# Generated deterministically by seda-macro-lef-normalizer-v1; recipe orfs-ng45-fakeram-metal3-coupledl2-pg-v1.
VERSION 5.8 ;
BUSBITCHARS "[]" ;
DIVIDERCHAR "/" ;

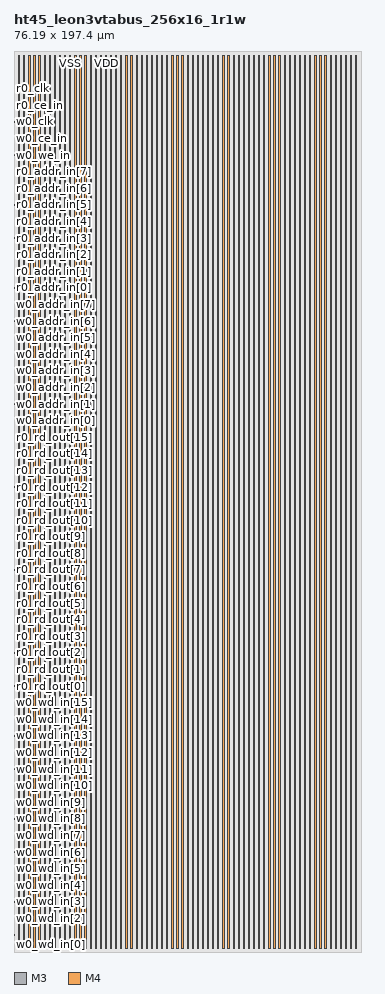
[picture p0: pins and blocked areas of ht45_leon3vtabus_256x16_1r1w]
MACRO ht45_leon3vtabus_256x16_1r1w
  FOREIGN ht45_leon3vtabus_256x16_1r1w 0 0 ;
  CLASS BLOCK ;
  ORIGIN 0 0 ;
  SIZE 76.19 BY 197.4 ;
  SYMMETRY X Y R90 ;
  PIN w0_wd_in[0]
    DIRECTION INPUT ;
    USE SIGNAL ;
    SHAPE ABUTMENT ;
    PORT
      LAYER M3 ;
      RECT 0 0.035 0.07 0.105 ;
    END
  END w0_wd_in[0]
  PIN w0_wd_in[1]
    DIRECTION INPUT ;
    USE SIGNAL ;
    SHAPE ABUTMENT ;
    PORT
      LAYER M3 ;
      RECT 0 3.675 0.07 3.745 ;
    END
  END w0_wd_in[1]
  PIN w0_wd_in[2]
    DIRECTION INPUT ;
    USE SIGNAL ;
    SHAPE ABUTMENT ;
    PORT
      LAYER M3 ;
      RECT 0 7.315 0.07 7.385 ;
    END
  END w0_wd_in[2]
  PIN w0_wd_in[3]
    DIRECTION INPUT ;
    USE SIGNAL ;
    SHAPE ABUTMENT ;
    PORT
      LAYER M3 ;
      RECT 0 10.955 0.07 11.025 ;
    END
  END w0_wd_in[3]
  PIN w0_wd_in[4]
    DIRECTION INPUT ;
    USE SIGNAL ;
    SHAPE ABUTMENT ;
    PORT
      LAYER M3 ;
      RECT 0 14.595 0.07 14.665 ;
    END
  END w0_wd_in[4]
  PIN w0_wd_in[5]
    DIRECTION INPUT ;
    USE SIGNAL ;
    SHAPE ABUTMENT ;
    PORT
      LAYER M3 ;
      RECT 0 18.235 0.07 18.305 ;
    END
  END w0_wd_in[5]
  PIN w0_wd_in[6]
    DIRECTION INPUT ;
    USE SIGNAL ;
    SHAPE ABUTMENT ;
    PORT
      LAYER M3 ;
      RECT 0 21.875 0.07 21.945 ;
    END
  END w0_wd_in[6]
  PIN w0_wd_in[7]
    DIRECTION INPUT ;
    USE SIGNAL ;
    SHAPE ABUTMENT ;
    PORT
      LAYER M3 ;
      RECT 0 25.515 0.07 25.585 ;
    END
  END w0_wd_in[7]
  PIN w0_wd_in[8]
    DIRECTION INPUT ;
    USE SIGNAL ;
    SHAPE ABUTMENT ;
    PORT
      LAYER M3 ;
      RECT 0 29.155 0.07 29.225 ;
    END
  END w0_wd_in[8]
  PIN w0_wd_in[9]
    DIRECTION INPUT ;
    USE SIGNAL ;
    SHAPE ABUTMENT ;
    PORT
      LAYER M3 ;
      RECT 0 32.795 0.07 32.865 ;
    END
  END w0_wd_in[9]
  PIN w0_wd_in[10]
    DIRECTION INPUT ;
    USE SIGNAL ;
    SHAPE ABUTMENT ;
    PORT
      LAYER M3 ;
      RECT 0 36.435 0.07 36.505 ;
    END
  END w0_wd_in[10]
  PIN w0_wd_in[11]
    DIRECTION INPUT ;
    USE SIGNAL ;
    SHAPE ABUTMENT ;
    PORT
      LAYER M3 ;
      RECT 0 40.075 0.07 40.145 ;
    END
  END w0_wd_in[11]
  PIN w0_wd_in[12]
    DIRECTION INPUT ;
    USE SIGNAL ;
    SHAPE ABUTMENT ;
    PORT
      LAYER M3 ;
      RECT 0 43.715 0.07 43.785 ;
    END
  END w0_wd_in[12]
  PIN w0_wd_in[13]
    DIRECTION INPUT ;
    USE SIGNAL ;
    SHAPE ABUTMENT ;
    PORT
      LAYER M3 ;
      RECT 0 47.355 0.07 47.425 ;
    END
  END w0_wd_in[13]
  PIN w0_wd_in[14]
    DIRECTION INPUT ;
    USE SIGNAL ;
    SHAPE ABUTMENT ;
    PORT
      LAYER M3 ;
      RECT 0 50.995 0.07 51.065 ;
    END
  END w0_wd_in[14]
  PIN w0_wd_in[15]
    DIRECTION INPUT ;
    USE SIGNAL ;
    SHAPE ABUTMENT ;
    PORT
      LAYER M3 ;
      RECT 0 54.635 0.07 54.705 ;
    END
  END w0_wd_in[15]
  PIN r0_rd_out[0]
    DIRECTION OUTPUT ;
    USE SIGNAL ;
    SHAPE ABUTMENT ;
    PORT
      LAYER M3 ;
      RECT 0 58.275 0.07 58.345 ;
    END
  END r0_rd_out[0]
  PIN r0_rd_out[1]
    DIRECTION OUTPUT ;
    USE SIGNAL ;
    SHAPE ABUTMENT ;
    PORT
      LAYER M3 ;
      RECT 0 61.915 0.07 61.985 ;
    END
  END r0_rd_out[1]
  PIN r0_rd_out[2]
    DIRECTION OUTPUT ;
    USE SIGNAL ;
    SHAPE ABUTMENT ;
    PORT
      LAYER M3 ;
      RECT 0 65.555 0.07 65.625 ;
    END
  END r0_rd_out[2]
  PIN r0_rd_out[3]
    DIRECTION OUTPUT ;
    USE SIGNAL ;
    SHAPE ABUTMENT ;
    PORT
      LAYER M3 ;
      RECT 0 69.195 0.07 69.265 ;
    END
  END r0_rd_out[3]
  PIN r0_rd_out[4]
    DIRECTION OUTPUT ;
    USE SIGNAL ;
    SHAPE ABUTMENT ;
    PORT
      LAYER M3 ;
      RECT 0 72.835 0.07 72.905 ;
    END
  END r0_rd_out[4]
  PIN r0_rd_out[5]
    DIRECTION OUTPUT ;
    USE SIGNAL ;
    SHAPE ABUTMENT ;
    PORT
      LAYER M3 ;
      RECT 0 76.475 0.07 76.545 ;
    END
  END r0_rd_out[5]
  PIN r0_rd_out[6]
    DIRECTION OUTPUT ;
    USE SIGNAL ;
    SHAPE ABUTMENT ;
    PORT
      LAYER M3 ;
      RECT 0 80.115 0.07 80.185 ;
    END
  END r0_rd_out[6]
  PIN r0_rd_out[7]
    DIRECTION OUTPUT ;
    USE SIGNAL ;
    SHAPE ABUTMENT ;
    PORT
      LAYER M3 ;
      RECT 0 83.755 0.07 83.825 ;
    END
  END r0_rd_out[7]
  PIN r0_rd_out[8]
    DIRECTION OUTPUT ;
    USE SIGNAL ;
    SHAPE ABUTMENT ;
    PORT
      LAYER M3 ;
      RECT 0 87.395 0.07 87.465 ;
    END
  END r0_rd_out[8]
  PIN r0_rd_out[9]
    DIRECTION OUTPUT ;
    USE SIGNAL ;
    SHAPE ABUTMENT ;
    PORT
      LAYER M3 ;
      RECT 0 91.035 0.07 91.105 ;
    END
  END r0_rd_out[9]
  PIN r0_rd_out[10]
    DIRECTION OUTPUT ;
    USE SIGNAL ;
    SHAPE ABUTMENT ;
    PORT
      LAYER M3 ;
      RECT 0 94.675 0.07 94.745 ;
    END
  END r0_rd_out[10]
  PIN r0_rd_out[11]
    DIRECTION OUTPUT ;
    USE SIGNAL ;
    SHAPE ABUTMENT ;
    PORT
      LAYER M3 ;
      RECT 0 98.315 0.07 98.385 ;
    END
  END r0_rd_out[11]
  PIN r0_rd_out[12]
    DIRECTION OUTPUT ;
    USE SIGNAL ;
    SHAPE ABUTMENT ;
    PORT
      LAYER M3 ;
      RECT 0 101.955 0.07 102.025 ;
    END
  END r0_rd_out[12]
  PIN r0_rd_out[13]
    DIRECTION OUTPUT ;
    USE SIGNAL ;
    SHAPE ABUTMENT ;
    PORT
      LAYER M3 ;
      RECT 0 105.595 0.07 105.665 ;
    END
  END r0_rd_out[13]
  PIN r0_rd_out[14]
    DIRECTION OUTPUT ;
    USE SIGNAL ;
    SHAPE ABUTMENT ;
    PORT
      LAYER M3 ;
      RECT 0 109.235 0.07 109.305 ;
    END
  END r0_rd_out[14]
  PIN r0_rd_out[15]
    DIRECTION OUTPUT ;
    USE SIGNAL ;
    SHAPE ABUTMENT ;
    PORT
      LAYER M3 ;
      RECT 0 112.875 0.07 112.945 ;
    END
  END r0_rd_out[15]
  PIN w0_addr_in[0]
    DIRECTION INPUT ;
    USE SIGNAL ;
    SHAPE ABUTMENT ;
    PORT
      LAYER M3 ;
      RECT 0 116.515 0.07 116.585 ;
    END
  END w0_addr_in[0]
  PIN w0_addr_in[1]
    DIRECTION INPUT ;
    USE SIGNAL ;
    SHAPE ABUTMENT ;
    PORT
      LAYER M3 ;
      RECT 0 120.155 0.07 120.225 ;
    END
  END w0_addr_in[1]
  PIN w0_addr_in[2]
    DIRECTION INPUT ;
    USE SIGNAL ;
    SHAPE ABUTMENT ;
    PORT
      LAYER M3 ;
      RECT 0 123.795 0.07 123.865 ;
    END
  END w0_addr_in[2]
  PIN w0_addr_in[3]
    DIRECTION INPUT ;
    USE SIGNAL ;
    SHAPE ABUTMENT ;
    PORT
      LAYER M3 ;
      RECT 0 127.435 0.07 127.505 ;
    END
  END w0_addr_in[3]
  PIN w0_addr_in[4]
    DIRECTION INPUT ;
    USE SIGNAL ;
    SHAPE ABUTMENT ;
    PORT
      LAYER M3 ;
      RECT 0 131.075 0.07 131.145 ;
    END
  END w0_addr_in[4]
  PIN w0_addr_in[5]
    DIRECTION INPUT ;
    USE SIGNAL ;
    SHAPE ABUTMENT ;
    PORT
      LAYER M3 ;
      RECT 0 134.715 0.07 134.785 ;
    END
  END w0_addr_in[5]
  PIN w0_addr_in[6]
    DIRECTION INPUT ;
    USE SIGNAL ;
    SHAPE ABUTMENT ;
    PORT
      LAYER M3 ;
      RECT 0 138.355 0.07 138.425 ;
    END
  END w0_addr_in[6]
  PIN w0_addr_in[7]
    DIRECTION INPUT ;
    USE SIGNAL ;
    SHAPE ABUTMENT ;
    PORT
      LAYER M3 ;
      RECT 0 141.995 0.07 142.065 ;
    END
  END w0_addr_in[7]
  PIN r0_addr_in[0]
    DIRECTION INPUT ;
    USE SIGNAL ;
    SHAPE ABUTMENT ;
    PORT
      LAYER M3 ;
      RECT 0 145.635 0.07 145.705 ;
    END
  END r0_addr_in[0]
  PIN r0_addr_in[1]
    DIRECTION INPUT ;
    USE SIGNAL ;
    SHAPE ABUTMENT ;
    PORT
      LAYER M3 ;
      RECT 0 149.275 0.07 149.345 ;
    END
  END r0_addr_in[1]
  PIN r0_addr_in[2]
    DIRECTION INPUT ;
    USE SIGNAL ;
    SHAPE ABUTMENT ;
    PORT
      LAYER M3 ;
      RECT 0 152.915 0.07 152.985 ;
    END
  END r0_addr_in[2]
  PIN r0_addr_in[3]
    DIRECTION INPUT ;
    USE SIGNAL ;
    SHAPE ABUTMENT ;
    PORT
      LAYER M3 ;
      RECT 0 156.555 0.07 156.625 ;
    END
  END r0_addr_in[3]
  PIN r0_addr_in[4]
    DIRECTION INPUT ;
    USE SIGNAL ;
    SHAPE ABUTMENT ;
    PORT
      LAYER M3 ;
      RECT 0 160.195 0.07 160.265 ;
    END
  END r0_addr_in[4]
  PIN r0_addr_in[5]
    DIRECTION INPUT ;
    USE SIGNAL ;
    SHAPE ABUTMENT ;
    PORT
      LAYER M3 ;
      RECT 0 163.835 0.07 163.905 ;
    END
  END r0_addr_in[5]
  PIN r0_addr_in[6]
    DIRECTION INPUT ;
    USE SIGNAL ;
    SHAPE ABUTMENT ;
    PORT
      LAYER M3 ;
      RECT 0 167.475 0.07 167.545 ;
    END
  END r0_addr_in[6]
  PIN r0_addr_in[7]
    DIRECTION INPUT ;
    USE SIGNAL ;
    SHAPE ABUTMENT ;
    PORT
      LAYER M3 ;
      RECT 0 171.115 0.07 171.185 ;
    END
  END r0_addr_in[7]
  PIN w0_we_in
    DIRECTION INPUT ;
    USE SIGNAL ;
    SHAPE ABUTMENT ;
    PORT
      LAYER M3 ;
      RECT 0 174.755 0.07 174.825 ;
    END
  END w0_we_in
  PIN w0_ce_in
    DIRECTION INPUT ;
    USE SIGNAL ;
    SHAPE ABUTMENT ;
    PORT
      LAYER M3 ;
      RECT 0 178.395 0.07 178.465 ;
    END
  END w0_ce_in
  PIN w0_clk
    DIRECTION INPUT ;
    USE SIGNAL ;
    SHAPE ABUTMENT ;
    PORT
      LAYER M3 ;
      RECT 0 182.035 0.07 182.105 ;
    END
  END w0_clk
  PIN r0_ce_in
    DIRECTION INPUT ;
    USE SIGNAL ;
    SHAPE ABUTMENT ;
    PORT
      LAYER M3 ;
      RECT 0 185.675 0.07 185.745 ;
    END
  END r0_ce_in
  PIN r0_clk
    DIRECTION INPUT ;
    USE SIGNAL ;
    SHAPE ABUTMENT ;
    PORT
      LAYER M3 ;
      RECT 0 189.315 0.07 189.385 ;
    END
  END r0_clk
  PIN VSS
    DIRECTION INOUT ;
    USE GROUND ;
    PORT
      LAYER M4 ;
      RECT 1 0.84 1.28 196.56 ;
      RECT 3.24 0.84 3.52 196.56 ;
      RECT 5.48 0.84 5.76 196.56 ;
      RECT 7.72 0.84 8 196.56 ;
      RECT 9.96 0.84 10.24 196.56 ;
      RECT 12.2 0.84 12.48 196.56 ;
      RECT 14.44 0.84 14.72 196.56 ;
      RECT 16.68 0.84 16.96 196.56 ;
      RECT 18.92 0.84 19.2 196.56 ;
      RECT 21.16 0.84 21.44 196.56 ;
      RECT 23.4 0.84 23.68 196.56 ;
      RECT 25.64 0.84 25.92 196.56 ;
      RECT 27.88 0.84 28.16 196.56 ;
      RECT 30.12 0.84 30.4 196.56 ;
      RECT 32.36 0.84 32.64 196.56 ;
      RECT 34.6 0.84 34.88 196.56 ;
      RECT 36.84 0.84 37.12 196.56 ;
      RECT 39.08 0.84 39.36 196.56 ;
      RECT 41.32 0.84 41.6 196.56 ;
      RECT 43.56 0.84 43.84 196.56 ;
      RECT 45.8 0.84 46.08 196.56 ;
      RECT 48.04 0.84 48.32 196.56 ;
      RECT 50.28 0.84 50.56 196.56 ;
      RECT 52.52 0.84 52.8 196.56 ;
      RECT 54.76 0.84 55.04 196.56 ;
      RECT 57 0.84 57.28 196.56 ;
      RECT 59.24 0.84 59.52 196.56 ;
      RECT 61.48 0.84 61.76 196.56 ;
      RECT 63.72 0.84 64 196.56 ;
      RECT 65.96 0.84 66.24 196.56 ;
      RECT 68.2 0.84 68.48 196.56 ;
      RECT 70.44 0.84 70.72 196.56 ;
      RECT 72.68 0.84 72.96 196.56 ;
      RECT 74.92 0.84 75.2 196.56 ;
    END
  END VSS
  PIN VDD
    DIRECTION INOUT ;
    USE POWER ;
    PORT
      LAYER M4 ;
      RECT 2.12 0.84 2.4 196.56 ;
      RECT 4.36 0.84 4.64 196.56 ;
      RECT 6.6 0.84 6.88 196.56 ;
      RECT 8.84 0.84 9.12 196.56 ;
      RECT 11.08 0.84 11.36 196.56 ;
      RECT 13.32 0.84 13.6 196.56 ;
      RECT 15.56 0.84 15.84 196.56 ;
      RECT 17.8 0.84 18.08 196.56 ;
      RECT 20.04 0.84 20.32 196.56 ;
      RECT 22.28 0.84 22.56 196.56 ;
      RECT 24.52 0.84 24.8 196.56 ;
      RECT 26.76 0.84 27.04 196.56 ;
      RECT 29 0.84 29.28 196.56 ;
      RECT 31.24 0.84 31.52 196.56 ;
      RECT 33.48 0.84 33.76 196.56 ;
      RECT 35.72 0.84 36 196.56 ;
      RECT 37.96 0.84 38.24 196.56 ;
      RECT 40.2 0.84 40.48 196.56 ;
      RECT 42.44 0.84 42.72 196.56 ;
      RECT 44.68 0.84 44.96 196.56 ;
      RECT 46.92 0.84 47.2 196.56 ;
      RECT 49.16 0.84 49.44 196.56 ;
      RECT 51.4 0.84 51.68 196.56 ;
      RECT 53.64 0.84 53.92 196.56 ;
      RECT 55.88 0.84 56.16 196.56 ;
      RECT 58.12 0.84 58.4 196.56 ;
      RECT 60.36 0.84 60.64 196.56 ;
      RECT 62.6 0.84 62.88 196.56 ;
      RECT 64.84 0.84 65.12 196.56 ;
      RECT 67.08 0.84 67.36 196.56 ;
      RECT 69.32 0.84 69.6 196.56 ;
      RECT 71.56 0.84 71.84 196.56 ;
      RECT 73.8 0.84 74.08 196.56 ;
    END
  END VDD
  OBS
    LAYER M1 ;
    RECT 0 0 76.19 197.4 ;
    LAYER M2 ;
    RECT 0 0 76.19 197.4 ;
  END
END ht45_leon3vtabus_256x16_1r1w

END LIBRARY
